VERSION 5.7 ;
  NOWIREEXTENSIONATPIN ON ;
  DIVIDERCHAR "/" ;
  BUSBITCHARS "[]" ;
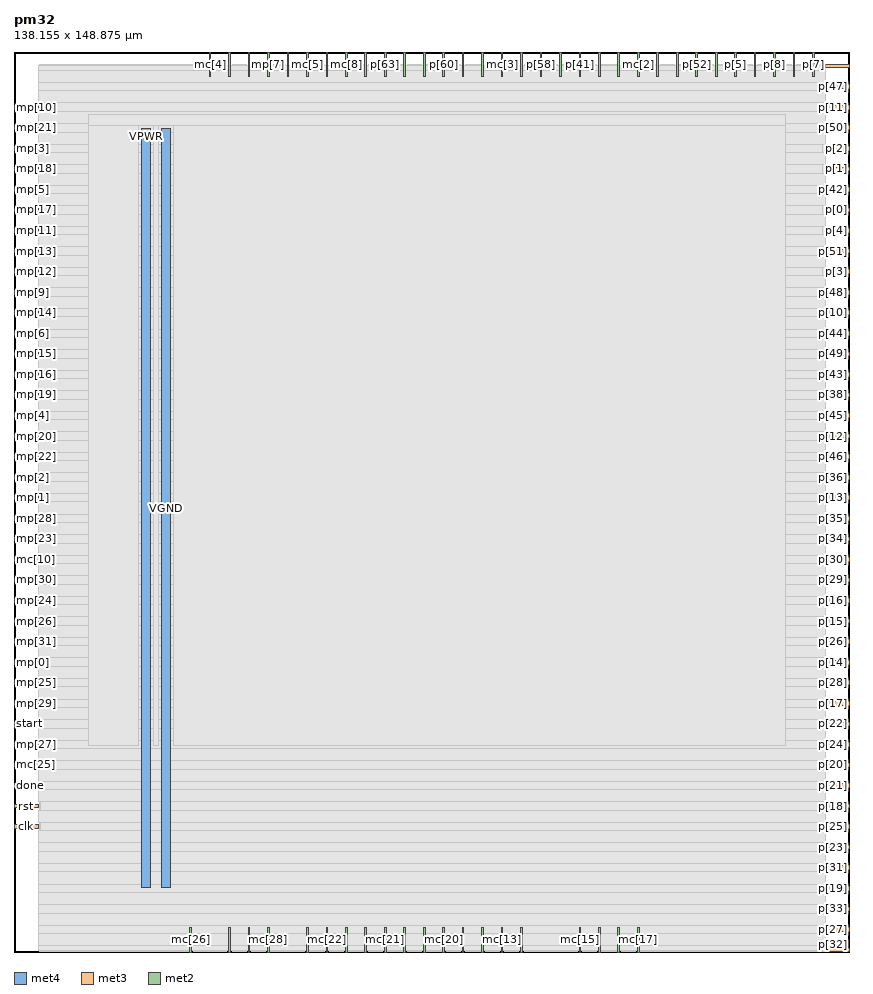
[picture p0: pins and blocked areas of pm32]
MACRO pm32
  CLASS BLOCK ;
  FOREIGN pm32 ;
  ORIGIN 0.000 0.000 ;
  SIZE 138.155 BY 148.875 ;
  PIN VGND
    DIRECTION INOUT ;
    USE GROUND ;
    PORT
      LAYER met4 ;
        RECT 24.340 10.640 25.940 136.240 ;
    END
  END VGND
  PIN VPWR
    DIRECTION INOUT ;
    USE POWER ;
    PORT
      LAYER met4 ;
        RECT 21.040 10.640 22.640 136.240 ;
    END
  END VPWR
  PIN clk
    DIRECTION INPUT ;
    USE SIGNAL ;
    ANTENNAGATEAREA 0.852000 ;
    PORT
      LAYER met3 ;
        RECT 0.000 20.440 4.000 21.040 ;
    END
  END clk
  PIN done
    DIRECTION OUTPUT ;
    USE SIGNAL ;
    ANTENNADIFFAREA 0.445500 ;
    PORT
      LAYER met3 ;
        RECT 0.000 27.240 4.000 27.840 ;
    END
  END done
  PIN mc[0]
    DIRECTION INPUT ;
    USE SIGNAL ;
    ANTENNAGATEAREA 0.196500 ;
    PORT
      LAYER met2 ;
        RECT 74.150 144.875 74.430 148.875 ;
    END
  END mc[0]
  PIN mc[10]
    DIRECTION INPUT ;
    USE SIGNAL ;
    ANTENNAGATEAREA 0.196500 ;
    PORT
      LAYER met3 ;
        RECT 0.000 64.640 4.000 65.240 ;
    END
  END mc[10]
  PIN mc[11]
    DIRECTION INPUT ;
    USE SIGNAL ;
    ANTENNAGATEAREA 0.196500 ;
    PORT
      LAYER met2 ;
        RECT 58.050 0.000 58.330 4.000 ;
    END
  END mc[11]
  PIN mc[12]
    DIRECTION INPUT ;
    USE SIGNAL ;
    ANTENNAGATEAREA 0.196500 ;
    PORT
      LAYER met2 ;
        RECT 74.150 0.000 74.430 4.000 ;
    END
  END mc[12]
  PIN mc[13]
    DIRECTION INPUT ;
    USE SIGNAL ;
    ANTENNAGATEAREA 0.196500 ;
    PORT
      LAYER met2 ;
        RECT 80.590 0.000 80.870 4.000 ;
    END
  END mc[13]
  PIN mc[14]
    DIRECTION INPUT ;
    USE SIGNAL ;
    ANTENNAGATEAREA 0.196500 ;
    PORT
      LAYER met2 ;
        RECT 77.370 0.000 77.650 4.000 ;
    END
  END mc[14]
  PIN mc[15]
    DIRECTION INPUT ;
    USE SIGNAL ;
    ANTENNAGATEAREA 0.196500 ;
    PORT
      LAYER met2 ;
        RECT 93.470 0.000 93.750 4.000 ;
    END
  END mc[15]
  PIN mc[16]
    DIRECTION INPUT ;
    USE SIGNAL ;
    ANTENNAGATEAREA 0.196500 ;
    PORT
      LAYER met2 ;
        RECT 99.910 0.000 100.190 4.000 ;
    END
  END mc[16]
  PIN mc[17]
    DIRECTION INPUT ;
    USE SIGNAL ;
    ANTENNAGATEAREA 0.196500 ;
    PORT
      LAYER met2 ;
        RECT 103.130 0.000 103.410 4.000 ;
    END
  END mc[17]
  PIN mc[18]
    DIRECTION INPUT ;
    USE SIGNAL ;
    ANTENNAGATEAREA 0.196500 ;
    PORT
      LAYER met2 ;
        RECT 96.690 0.000 96.970 4.000 ;
    END
  END mc[18]
  PIN mc[19]
    DIRECTION INPUT ;
    USE SIGNAL ;
    ANTENNAGATEAREA 0.196500 ;
    PORT
      LAYER met2 ;
        RECT 83.810 0.000 84.090 4.000 ;
    END
  END mc[19]
  PIN mc[1]
    DIRECTION INPUT ;
    USE SIGNAL ;
    ANTENNAGATEAREA 0.196500 ;
    PORT
      LAYER met2 ;
        RECT 116.010 144.875 116.290 148.875 ;
    END
  END mc[1]
  PIN mc[20]
    DIRECTION INPUT ;
    USE SIGNAL ;
    ANTENNAGATEAREA 0.196500 ;
    PORT
      LAYER met2 ;
        RECT 70.930 0.000 71.210 4.000 ;
    END
  END mc[20]
  PIN mc[21]
    DIRECTION INPUT ;
    USE SIGNAL ;
    ANTENNAGATEAREA 0.196500 ;
    PORT
      LAYER met2 ;
        RECT 61.270 0.000 61.550 4.000 ;
    END
  END mc[21]
  PIN mc[22]
    DIRECTION INPUT ;
    USE SIGNAL ;
    ANTENNAGATEAREA 0.196500 ;
    PORT
      LAYER met2 ;
        RECT 51.610 0.000 51.890 4.000 ;
    END
  END mc[22]
  PIN mc[23]
    DIRECTION INPUT ;
    USE SIGNAL ;
    ANTENNAGATEAREA 0.196500 ;
    PORT
      LAYER met2 ;
        RECT 48.390 0.000 48.670 4.000 ;
    END
  END mc[23]
  PIN mc[24]
    DIRECTION INPUT ;
    USE SIGNAL ;
    ANTENNAGATEAREA 0.196500 ;
    PORT
      LAYER met2 ;
        RECT 35.510 0.000 35.790 4.000 ;
    END
  END mc[24]
  PIN mc[25]
    DIRECTION INPUT ;
    USE SIGNAL ;
    ANTENNAGATEAREA 0.196500 ;
    PORT
      LAYER met3 ;
        RECT 0.000 30.640 4.000 31.240 ;
    END
  END mc[25]
  PIN mc[26]
    DIRECTION INPUT ;
    USE SIGNAL ;
    ANTENNAGATEAREA 0.196500 ;
    PORT
      LAYER met2 ;
        RECT 29.070 0.000 29.350 4.000 ;
    END
  END mc[26]
  PIN mc[27]
    DIRECTION INPUT ;
    USE SIGNAL ;
    ANTENNAGATEAREA 0.196500 ;
    PORT
      LAYER met2 ;
        RECT 38.730 0.000 39.010 4.000 ;
    END
  END mc[27]
  PIN mc[28]
    DIRECTION INPUT ;
    USE SIGNAL ;
    ANTENNAGATEAREA 0.196500 ;
    PORT
      LAYER met2 ;
        RECT 41.950 0.000 42.230 4.000 ;
    END
  END mc[28]
  PIN mc[29]
    DIRECTION INPUT ;
    USE SIGNAL ;
    ANTENNAGATEAREA 0.196500 ;
    PORT
      LAYER met2 ;
        RECT 67.710 0.000 67.990 4.000 ;
    END
  END mc[29]
  PIN mc[2]
    DIRECTION INPUT ;
    USE SIGNAL ;
    ANTENNAGATEAREA 0.196500 ;
    PORT
      LAYER met2 ;
        RECT 103.130 144.875 103.410 148.875 ;
    END
  END mc[2]
  PIN mc[30]
    DIRECTION INPUT ;
    USE SIGNAL ;
    ANTENNAGATEAREA 0.196500 ;
    PORT
      LAYER met2 ;
        RECT 64.490 0.000 64.770 4.000 ;
    END
  END mc[30]
  PIN mc[31]
    DIRECTION INPUT ;
    USE SIGNAL ;
    ANTENNAGATEAREA 0.196500 ;
    PORT
      LAYER met2 ;
        RECT 54.830 0.000 55.110 4.000 ;
    END
  END mc[31]
  PIN mc[3]
    DIRECTION INPUT ;
    USE SIGNAL ;
    ANTENNAGATEAREA 0.196500 ;
    PORT
      LAYER met2 ;
        RECT 80.590 144.875 80.870 148.875 ;
    END
  END mc[3]
  PIN mc[4]
    DIRECTION INPUT ;
    USE SIGNAL ;
    ANTENNAGATEAREA 0.196500 ;
    PORT
      LAYER met2 ;
        RECT 32.290 144.875 32.570 148.875 ;
    END
  END mc[4]
  PIN mc[5]
    DIRECTION INPUT ;
    USE SIGNAL ;
    ANTENNAGATEAREA 0.196500 ;
    PORT
      LAYER met2 ;
        RECT 48.390 144.875 48.670 148.875 ;
    END
  END mc[5]
  PIN mc[6]
    DIRECTION INPUT ;
    USE SIGNAL ;
    ANTENNAGATEAREA 0.196500 ;
    PORT
      LAYER met2 ;
        RECT 38.730 144.875 39.010 148.875 ;
    END
  END mc[6]
  PIN mc[7]
    DIRECTION INPUT ;
    USE SIGNAL ;
    ANTENNAGATEAREA 0.196500 ;
    PORT
      LAYER met2 ;
        RECT 45.170 144.875 45.450 148.875 ;
    END
  END mc[7]
  PIN mc[8]
    DIRECTION INPUT ;
    USE SIGNAL ;
    ANTENNAGATEAREA 0.196500 ;
    PORT
      LAYER met2 ;
        RECT 54.830 144.875 55.110 148.875 ;
    END
  END mc[8]
  PIN mc[9]
    DIRECTION INPUT ;
    USE SIGNAL ;
    ANTENNAGATEAREA 0.196500 ;
    PORT
      LAYER met2 ;
        RECT 58.050 144.875 58.330 148.875 ;
    END
  END mc[9]
  PIN mp[0]
    DIRECTION INPUT ;
    USE SIGNAL ;
    ANTENNAGATEAREA 0.196500 ;
    PORT
      LAYER met3 ;
        RECT 0.000 47.640 4.000 48.240 ;
    END
  END mp[0]
  PIN mp[10]
    DIRECTION INPUT ;
    USE SIGNAL ;
    ANTENNAGATEAREA 0.196500 ;
    PORT
      LAYER met3 ;
        RECT 0.000 139.440 4.000 140.040 ;
    END
  END mp[10]
  PIN mp[11]
    DIRECTION INPUT ;
    USE SIGNAL ;
    ANTENNAGATEAREA 0.196500 ;
    PORT
      LAYER met3 ;
        RECT 0.000 119.040 4.000 119.640 ;
    END
  END mp[11]
  PIN mp[12]
    DIRECTION INPUT ;
    USE SIGNAL ;
    ANTENNAGATEAREA 0.196500 ;
    PORT
      LAYER met3 ;
        RECT 0.000 112.240 4.000 112.840 ;
    END
  END mp[12]
  PIN mp[13]
    DIRECTION INPUT ;
    USE SIGNAL ;
    ANTENNAGATEAREA 0.196500 ;
    PORT
      LAYER met3 ;
        RECT 0.000 115.640 4.000 116.240 ;
    END
  END mp[13]
  PIN mp[14]
    DIRECTION INPUT ;
    USE SIGNAL ;
    ANTENNAGATEAREA 0.196500 ;
    PORT
      LAYER met3 ;
        RECT 0.000 105.440 4.000 106.040 ;
    END
  END mp[14]
  PIN mp[15]
    DIRECTION INPUT ;
    USE SIGNAL ;
    ANTENNAGATEAREA 0.196500 ;
    PORT
      LAYER met3 ;
        RECT 0.000 98.640 4.000 99.240 ;
    END
  END mp[15]
  PIN mp[16]
    DIRECTION INPUT ;
    USE SIGNAL ;
    ANTENNAGATEAREA 0.196500 ;
    PORT
      LAYER met3 ;
        RECT 0.000 95.240 4.000 95.840 ;
    END
  END mp[16]
  PIN mp[17]
    DIRECTION INPUT ;
    USE SIGNAL ;
    ANTENNAGATEAREA 0.196500 ;
    PORT
      LAYER met3 ;
        RECT 0.000 122.440 4.000 123.040 ;
    END
  END mp[17]
  PIN mp[18]
    DIRECTION INPUT ;
    USE SIGNAL ;
    ANTENNAGATEAREA 0.196500 ;
    PORT
      LAYER met3 ;
        RECT 0.000 129.240 4.000 129.840 ;
    END
  END mp[18]
  PIN mp[19]
    DIRECTION INPUT ;
    USE SIGNAL ;
    ANTENNAGATEAREA 0.196500 ;
    PORT
      LAYER met3 ;
        RECT 0.000 91.840 4.000 92.440 ;
    END
  END mp[19]
  PIN mp[1]
    DIRECTION INPUT ;
    USE SIGNAL ;
    ANTENNAGATEAREA 0.196500 ;
    PORT
      LAYER met3 ;
        RECT 0.000 74.840 4.000 75.440 ;
    END
  END mp[1]
  PIN mp[20]
    DIRECTION INPUT ;
    USE SIGNAL ;
    ANTENNAGATEAREA 0.196500 ;
    PORT
      LAYER met3 ;
        RECT 0.000 85.040 4.000 85.640 ;
    END
  END mp[20]
  PIN mp[21]
    DIRECTION INPUT ;
    USE SIGNAL ;
    ANTENNAGATEAREA 0.196500 ;
    PORT
      LAYER met3 ;
        RECT 0.000 136.040 4.000 136.640 ;
    END
  END mp[21]
  PIN mp[22]
    DIRECTION INPUT ;
    USE SIGNAL ;
    ANTENNAGATEAREA 0.196500 ;
    PORT
      LAYER met3 ;
        RECT 0.000 81.640 4.000 82.240 ;
    END
  END mp[22]
  PIN mp[23]
    DIRECTION INPUT ;
    USE SIGNAL ;
    ANTENNAGATEAREA 0.196500 ;
    PORT
      LAYER met3 ;
        RECT 0.000 68.040 4.000 68.640 ;
    END
  END mp[23]
  PIN mp[24]
    DIRECTION INPUT ;
    USE SIGNAL ;
    ANTENNAGATEAREA 0.196500 ;
    PORT
      LAYER met3 ;
        RECT 0.000 57.840 4.000 58.440 ;
    END
  END mp[24]
  PIN mp[25]
    DIRECTION INPUT ;
    USE SIGNAL ;
    ANTENNAGATEAREA 0.196500 ;
    PORT
      LAYER met3 ;
        RECT 0.000 44.240 4.000 44.840 ;
    END
  END mp[25]
  PIN mp[26]
    DIRECTION INPUT ;
    USE SIGNAL ;
    ANTENNAGATEAREA 0.196500 ;
    PORT
      LAYER met3 ;
        RECT 0.000 54.440 4.000 55.040 ;
    END
  END mp[26]
  PIN mp[27]
    DIRECTION INPUT ;
    USE SIGNAL ;
    ANTENNAGATEAREA 0.196500 ;
    PORT
      LAYER met3 ;
        RECT 0.000 34.040 4.000 34.640 ;
    END
  END mp[27]
  PIN mp[28]
    DIRECTION INPUT ;
    USE SIGNAL ;
    ANTENNAGATEAREA 0.196500 ;
    PORT
      LAYER met3 ;
        RECT 0.000 71.440 4.000 72.040 ;
    END
  END mp[28]
  PIN mp[29]
    DIRECTION INPUT ;
    USE SIGNAL ;
    ANTENNAGATEAREA 0.196500 ;
    PORT
      LAYER met3 ;
        RECT 0.000 40.840 4.000 41.440 ;
    END
  END mp[29]
  PIN mp[2]
    DIRECTION INPUT ;
    USE SIGNAL ;
    ANTENNAGATEAREA 0.196500 ;
    PORT
      LAYER met3 ;
        RECT 0.000 78.240 4.000 78.840 ;
    END
  END mp[2]
  PIN mp[30]
    DIRECTION INPUT ;
    USE SIGNAL ;
    ANTENNAGATEAREA 0.196500 ;
    PORT
      LAYER met3 ;
        RECT 0.000 61.240 4.000 61.840 ;
    END
  END mp[30]
  PIN mp[31]
    DIRECTION INPUT ;
    USE SIGNAL ;
    ANTENNAGATEAREA 0.196500 ;
    PORT
      LAYER met3 ;
        RECT 0.000 51.040 4.000 51.640 ;
    END
  END mp[31]
  PIN mp[3]
    DIRECTION INPUT ;
    USE SIGNAL ;
    ANTENNAGATEAREA 0.196500 ;
    PORT
      LAYER met3 ;
        RECT 0.000 132.640 4.000 133.240 ;
    END
  END mp[3]
  PIN mp[4]
    DIRECTION INPUT ;
    USE SIGNAL ;
    ANTENNAGATEAREA 0.196500 ;
    PORT
      LAYER met3 ;
        RECT 0.000 88.440 4.000 89.040 ;
    END
  END mp[4]
  PIN mp[5]
    DIRECTION INPUT ;
    USE SIGNAL ;
    ANTENNAGATEAREA 0.196500 ;
    PORT
      LAYER met3 ;
        RECT 0.000 125.840 4.000 126.440 ;
    END
  END mp[5]
  PIN mp[6]
    DIRECTION INPUT ;
    USE SIGNAL ;
    ANTENNAGATEAREA 0.196500 ;
    PORT
      LAYER met3 ;
        RECT 0.000 102.040 4.000 102.640 ;
    END
  END mp[6]
  PIN mp[7]
    DIRECTION INPUT ;
    USE SIGNAL ;
    ANTENNAGATEAREA 0.196500 ;
    PORT
      LAYER met2 ;
        RECT 41.950 144.875 42.230 148.875 ;
    END
  END mp[7]
  PIN mp[8]
    DIRECTION INPUT ;
    USE SIGNAL ;
    ANTENNAGATEAREA 0.196500 ;
    PORT
      LAYER met2 ;
        RECT 35.510 144.875 35.790 148.875 ;
    END
  END mp[8]
  PIN mp[9]
    DIRECTION INPUT ;
    USE SIGNAL ;
    ANTENNAGATEAREA 0.196500 ;
    PORT
      LAYER met3 ;
        RECT 0.000 108.840 4.000 109.440 ;
    END
  END mp[9]
  PIN p[0]
    DIRECTION OUTPUT ;
    USE SIGNAL ;
    ANTENNADIFFAREA 0.445500 ;
    PORT
      LAYER met3 ;
        RECT 134.155 122.440 138.155 123.040 ;
    END
  END p[0]
  PIN p[10]
    DIRECTION OUTPUT ;
    USE SIGNAL ;
    ANTENNADIFFAREA 0.445500 ;
    PORT
      LAYER met3 ;
        RECT 134.155 105.440 138.155 106.040 ;
    END
  END p[10]
  PIN p[11]
    DIRECTION OUTPUT ;
    USE SIGNAL ;
    ANTENNADIFFAREA 0.445500 ;
    PORT
      LAYER met3 ;
        RECT 134.155 139.440 138.155 140.040 ;
    END
  END p[11]
  PIN p[12]
    DIRECTION OUTPUT ;
    USE SIGNAL ;
    ANTENNADIFFAREA 0.445500 ;
    PORT
      LAYER met3 ;
        RECT 134.155 85.040 138.155 85.640 ;
    END
  END p[12]
  PIN p[13]
    DIRECTION OUTPUT ;
    USE SIGNAL ;
    ANTENNADIFFAREA 0.445500 ;
    PORT
      LAYER met3 ;
        RECT 134.155 74.840 138.155 75.440 ;
    END
  END p[13]
  PIN p[14]
    DIRECTION OUTPUT ;
    USE SIGNAL ;
    ANTENNADIFFAREA 0.445500 ;
    PORT
      LAYER met3 ;
        RECT 134.155 47.640 138.155 48.240 ;
    END
  END p[14]
  PIN p[15]
    DIRECTION OUTPUT ;
    USE SIGNAL ;
    ANTENNADIFFAREA 0.445500 ;
    PORT
      LAYER met3 ;
        RECT 134.155 54.440 138.155 55.040 ;
    END
  END p[15]
  PIN p[16]
    DIRECTION OUTPUT ;
    USE SIGNAL ;
    ANTENNADIFFAREA 0.445500 ;
    PORT
      LAYER met3 ;
        RECT 134.155 57.840 138.155 58.440 ;
    END
  END p[16]
  PIN p[17]
    DIRECTION OUTPUT ;
    USE SIGNAL ;
    ANTENNADIFFAREA 0.445500 ;
    PORT
      LAYER met3 ;
        RECT 134.155 40.840 138.155 41.440 ;
    END
  END p[17]
  PIN p[18]
    DIRECTION OUTPUT ;
    USE SIGNAL ;
    ANTENNADIFFAREA 0.445500 ;
    PORT
      LAYER met3 ;
        RECT 134.155 23.840 138.155 24.440 ;
    END
  END p[18]
  PIN p[19]
    DIRECTION OUTPUT ;
    USE SIGNAL ;
    ANTENNADIFFAREA 0.445500 ;
    PORT
      LAYER met3 ;
        RECT 134.155 10.240 138.155 10.840 ;
    END
  END p[19]
  PIN p[1]
    DIRECTION OUTPUT ;
    USE SIGNAL ;
    ANTENNADIFFAREA 0.445500 ;
    PORT
      LAYER met3 ;
        RECT 134.155 129.240 138.155 129.840 ;
    END
  END p[1]
  PIN p[20]
    DIRECTION OUTPUT ;
    USE SIGNAL ;
    ANTENNADIFFAREA 0.445500 ;
    PORT
      LAYER met3 ;
        RECT 134.155 30.640 138.155 31.240 ;
    END
  END p[20]
  PIN p[21]
    DIRECTION OUTPUT ;
    USE SIGNAL ;
    ANTENNADIFFAREA 0.445500 ;
    PORT
      LAYER met3 ;
        RECT 134.155 27.240 138.155 27.840 ;
    END
  END p[21]
  PIN p[22]
    DIRECTION OUTPUT ;
    USE SIGNAL ;
    ANTENNADIFFAREA 0.445500 ;
    PORT
      LAYER met3 ;
        RECT 134.155 37.440 138.155 38.040 ;
    END
  END p[22]
  PIN p[23]
    DIRECTION OUTPUT ;
    USE SIGNAL ;
    ANTENNADIFFAREA 0.445500 ;
    PORT
      LAYER met3 ;
        RECT 134.155 17.040 138.155 17.640 ;
    END
  END p[23]
  PIN p[24]
    DIRECTION OUTPUT ;
    USE SIGNAL ;
    ANTENNADIFFAREA 0.445500 ;
    PORT
      LAYER met3 ;
        RECT 134.155 34.040 138.155 34.640 ;
    END
  END p[24]
  PIN p[25]
    DIRECTION OUTPUT ;
    USE SIGNAL ;
    ANTENNADIFFAREA 0.445500 ;
    PORT
      LAYER met3 ;
        RECT 134.155 20.440 138.155 21.040 ;
    END
  END p[25]
  PIN p[26]
    DIRECTION OUTPUT ;
    USE SIGNAL ;
    ANTENNADIFFAREA 0.445500 ;
    PORT
      LAYER met3 ;
        RECT 134.155 51.040 138.155 51.640 ;
    END
  END p[26]
  PIN p[27]
    DIRECTION OUTPUT ;
    USE SIGNAL ;
    ANTENNADIFFAREA 0.445500 ;
    PORT
      LAYER met3 ;
        RECT 134.155 3.440 138.155 4.040 ;
    END
  END p[27]
  PIN p[28]
    DIRECTION OUTPUT ;
    USE SIGNAL ;
    ANTENNADIFFAREA 0.445500 ;
    PORT
      LAYER met3 ;
        RECT 134.155 44.240 138.155 44.840 ;
    END
  END p[28]
  PIN p[29]
    DIRECTION OUTPUT ;
    USE SIGNAL ;
    ANTENNADIFFAREA 0.445500 ;
    PORT
      LAYER met3 ;
        RECT 134.155 61.240 138.155 61.840 ;
    END
  END p[29]
  PIN p[2]
    DIRECTION OUTPUT ;
    USE SIGNAL ;
    ANTENNADIFFAREA 0.445500 ;
    PORT
      LAYER met3 ;
        RECT 134.155 132.640 138.155 133.240 ;
    END
  END p[2]
  PIN p[30]
    DIRECTION OUTPUT ;
    USE SIGNAL ;
    ANTENNADIFFAREA 0.445500 ;
    PORT
      LAYER met3 ;
        RECT 134.155 64.640 138.155 65.240 ;
    END
  END p[30]
  PIN p[31]
    DIRECTION OUTPUT ;
    USE SIGNAL ;
    ANTENNADIFFAREA 0.445500 ;
    PORT
      LAYER met3 ;
        RECT 134.155 13.640 138.155 14.240 ;
    END
  END p[31]
  PIN p[32]
    DIRECTION OUTPUT ;
    USE SIGNAL ;
    ANTENNADIFFAREA 0.445500 ;
    PORT
      LAYER met3 ;
        RECT 134.155 0.040 138.155 0.640 ;
    END
  END p[32]
  PIN p[33]
    DIRECTION OUTPUT ;
    USE SIGNAL ;
    ANTENNADIFFAREA 0.445500 ;
    PORT
      LAYER met3 ;
        RECT 134.155 6.840 138.155 7.440 ;
    END
  END p[33]
  PIN p[34]
    DIRECTION OUTPUT ;
    USE SIGNAL ;
    ANTENNADIFFAREA 0.445500 ;
    PORT
      LAYER met3 ;
        RECT 134.155 68.040 138.155 68.640 ;
    END
  END p[34]
  PIN p[35]
    DIRECTION OUTPUT ;
    USE SIGNAL ;
    ANTENNADIFFAREA 0.445500 ;
    PORT
      LAYER met3 ;
        RECT 134.155 71.440 138.155 72.040 ;
    END
  END p[35]
  PIN p[36]
    DIRECTION OUTPUT ;
    USE SIGNAL ;
    ANTENNADIFFAREA 0.445500 ;
    PORT
      LAYER met3 ;
        RECT 134.155 78.240 138.155 78.840 ;
    END
  END p[36]
  PIN p[37]
    DIRECTION OUTPUT ;
    USE SIGNAL ;
    ANTENNADIFFAREA 0.445500 ;
    PORT
      LAYER met3 ;
        RECT 134.155 146.240 138.155 146.840 ;
    END
  END p[37]
  PIN p[38]
    DIRECTION OUTPUT ;
    USE SIGNAL ;
    ANTENNADIFFAREA 0.445500 ;
    PORT
      LAYER met3 ;
        RECT 134.155 91.840 138.155 92.440 ;
    END
  END p[38]
  PIN p[39]
    DIRECTION OUTPUT ;
    USE SIGNAL ;
    ANTENNADIFFAREA 0.445500 ;
    PORT
      LAYER met2 ;
        RECT 77.370 144.875 77.650 148.875 ;
    END
  END p[39]
  PIN p[3]
    DIRECTION OUTPUT ;
    USE SIGNAL ;
    ANTENNADIFFAREA 0.445500 ;
    PORT
      LAYER met3 ;
        RECT 134.155 112.240 138.155 112.840 ;
    END
  END p[3]
  PIN p[40]
    DIRECTION OUTPUT ;
    USE SIGNAL ;
    ANTENNADIFFAREA 0.445500 ;
    PORT
      LAYER met2 ;
        RECT 51.610 144.875 51.890 148.875 ;
    END
  END p[40]
  PIN p[41]
    DIRECTION OUTPUT ;
    USE SIGNAL ;
    ANTENNADIFFAREA 0.445500 ;
    PORT
      LAYER met2 ;
        RECT 93.470 144.875 93.750 148.875 ;
    END
  END p[41]
  PIN p[42]
    DIRECTION OUTPUT ;
    USE SIGNAL ;
    ANTENNADIFFAREA 0.445500 ;
    PORT
      LAYER met3 ;
        RECT 134.155 125.840 138.155 126.440 ;
    END
  END p[42]
  PIN p[43]
    DIRECTION OUTPUT ;
    USE SIGNAL ;
    ANTENNADIFFAREA 0.445500 ;
    PORT
      LAYER met3 ;
        RECT 134.155 95.240 138.155 95.840 ;
    END
  END p[43]
  PIN p[44]
    DIRECTION OUTPUT ;
    USE SIGNAL ;
    ANTENNADIFFAREA 0.445500 ;
    PORT
      LAYER met3 ;
        RECT 134.155 102.040 138.155 102.640 ;
    END
  END p[44]
  PIN p[45]
    DIRECTION OUTPUT ;
    USE SIGNAL ;
    ANTENNADIFFAREA 0.445500 ;
    PORT
      LAYER met3 ;
        RECT 134.155 88.440 138.155 89.040 ;
    END
  END p[45]
  PIN p[46]
    DIRECTION OUTPUT ;
    USE SIGNAL ;
    ANTENNADIFFAREA 0.445500 ;
    PORT
      LAYER met3 ;
        RECT 134.155 81.640 138.155 82.240 ;
    END
  END p[46]
  PIN p[47]
    DIRECTION OUTPUT ;
    USE SIGNAL ;
    ANTENNADIFFAREA 0.445500 ;
    PORT
      LAYER met3 ;
        RECT 134.155 142.840 138.155 143.440 ;
    END
  END p[47]
  PIN p[48]
    DIRECTION OUTPUT ;
    USE SIGNAL ;
    ANTENNADIFFAREA 0.445500 ;
    PORT
      LAYER met3 ;
        RECT 134.155 108.840 138.155 109.440 ;
    END
  END p[48]
  PIN p[49]
    DIRECTION OUTPUT ;
    USE SIGNAL ;
    ANTENNADIFFAREA 0.445500 ;
    PORT
      LAYER met3 ;
        RECT 134.155 98.640 138.155 99.240 ;
    END
  END p[49]
  PIN p[4]
    DIRECTION OUTPUT ;
    USE SIGNAL ;
    ANTENNADIFFAREA 0.445500 ;
    PORT
      LAYER met3 ;
        RECT 134.155 119.040 138.155 119.640 ;
    END
  END p[4]
  PIN p[50]
    DIRECTION OUTPUT ;
    USE SIGNAL ;
    ANTENNADIFFAREA 0.445500 ;
    PORT
      LAYER met3 ;
        RECT 134.155 136.040 138.155 136.640 ;
    END
  END p[50]
  PIN p[51]
    DIRECTION OUTPUT ;
    USE SIGNAL ;
    ANTENNADIFFAREA 0.445500 ;
    PORT
      LAYER met3 ;
        RECT 134.155 115.640 138.155 116.240 ;
    END
  END p[51]
  PIN p[52]
    DIRECTION OUTPUT ;
    USE SIGNAL ;
    ANTENNADIFFAREA 0.445500 ;
    PORT
      LAYER met2 ;
        RECT 112.790 144.875 113.070 148.875 ;
    END
  END p[52]
  PIN p[53]
    DIRECTION OUTPUT ;
    USE SIGNAL ;
    ANTENNADIFFAREA 0.445500 ;
    PORT
      LAYER met2 ;
        RECT 109.570 144.875 109.850 148.875 ;
    END
  END p[53]
  PIN p[54]
    DIRECTION OUTPUT ;
    USE SIGNAL ;
    ANTENNADIFFAREA 0.445500 ;
    PORT
      LAYER met2 ;
        RECT 106.350 144.875 106.630 148.875 ;
    END
  END p[54]
  PIN p[55]
    DIRECTION OUTPUT ;
    USE SIGNAL ;
    ANTENNADIFFAREA 0.445500 ;
    PORT
      LAYER met2 ;
        RECT 99.910 144.875 100.190 148.875 ;
    END
  END p[55]
  PIN p[56]
    DIRECTION OUTPUT ;
    USE SIGNAL ;
    ANTENNADIFFAREA 0.445500 ;
    PORT
      LAYER met2 ;
        RECT 96.690 144.875 96.970 148.875 ;
    END
  END p[56]
  PIN p[57]
    DIRECTION OUTPUT ;
    USE SIGNAL ;
    ANTENNADIFFAREA 0.445500 ;
    PORT
      LAYER met2 ;
        RECT 90.250 144.875 90.530 148.875 ;
    END
  END p[57]
  PIN p[58]
    DIRECTION OUTPUT ;
    USE SIGNAL ;
    ANTENNADIFFAREA 0.445500 ;
    PORT
      LAYER met2 ;
        RECT 87.030 144.875 87.310 148.875 ;
    END
  END p[58]
  PIN p[59]
    DIRECTION OUTPUT ;
    USE SIGNAL ;
    ANTENNADIFFAREA 0.445500 ;
    PORT
      LAYER met2 ;
        RECT 83.810 144.875 84.090 148.875 ;
    END
  END p[59]
  PIN p[5]
    DIRECTION OUTPUT ;
    USE SIGNAL ;
    ANTENNADIFFAREA 0.445500 ;
    PORT
      LAYER met2 ;
        RECT 119.230 144.875 119.510 148.875 ;
    END
  END p[5]
  PIN p[60]
    DIRECTION OUTPUT ;
    USE SIGNAL ;
    ANTENNADIFFAREA 0.445500 ;
    PORT
      LAYER met2 ;
        RECT 70.930 144.875 71.210 148.875 ;
    END
  END p[60]
  PIN p[61]
    DIRECTION OUTPUT ;
    USE SIGNAL ;
    ANTENNADIFFAREA 0.445500 ;
    PORT
      LAYER met2 ;
        RECT 67.710 144.875 67.990 148.875 ;
    END
  END p[61]
  PIN p[62]
    DIRECTION OUTPUT ;
    USE SIGNAL ;
    ANTENNADIFFAREA 0.445500 ;
    PORT
      LAYER met2 ;
        RECT 64.490 144.875 64.770 148.875 ;
    END
  END p[62]
  PIN p[63]
    DIRECTION OUTPUT ;
    USE SIGNAL ;
    ANTENNADIFFAREA 0.445500 ;
    PORT
      LAYER met2 ;
        RECT 61.270 144.875 61.550 148.875 ;
    END
  END p[63]
  PIN p[6]
    DIRECTION OUTPUT ;
    USE SIGNAL ;
    ANTENNADIFFAREA 0.445500 ;
    PORT
      LAYER met2 ;
        RECT 128.890 144.875 129.170 148.875 ;
    END
  END p[6]
  PIN p[7]
    DIRECTION OUTPUT ;
    USE SIGNAL ;
    ANTENNADIFFAREA 0.445500 ;
    PORT
      LAYER met2 ;
        RECT 132.110 144.875 132.390 148.875 ;
    END
  END p[7]
  PIN p[8]
    DIRECTION OUTPUT ;
    USE SIGNAL ;
    ANTENNADIFFAREA 0.445500 ;
    PORT
      LAYER met2 ;
        RECT 125.670 144.875 125.950 148.875 ;
    END
  END p[8]
  PIN p[9]
    DIRECTION OUTPUT ;
    USE SIGNAL ;
    ANTENNADIFFAREA 0.445500 ;
    PORT
      LAYER met2 ;
        RECT 122.450 144.875 122.730 148.875 ;
    END
  END p[9]
  PIN rst
    DIRECTION INPUT ;
    USE SIGNAL ;
    ANTENNAGATEAREA 0.196500 ;
    PORT
      LAYER met3 ;
        RECT 0.000 23.840 4.000 24.440 ;
    END
  END rst
  PIN start
    DIRECTION INPUT ;
    USE SIGNAL ;
    ANTENNAGATEAREA 0.213000 ;
    PORT
      LAYER met3 ;
        RECT 0.000 37.440 4.000 38.040 ;
    END
  END start
  OBS
      LAYER nwell ;
        RECT 5.330 10.795 132.670 136.085 ;
      LAYER li1 ;
        RECT 5.520 10.795 132.480 136.085 ;
      LAYER met1 ;
        RECT 4.210 8.880 134.250 144.800 ;
      LAYER met2 ;
        RECT 4.230 144.595 32.010 146.725 ;
        RECT 32.850 144.595 35.230 146.725 ;
        RECT 36.070 144.595 38.450 146.725 ;
        RECT 39.290 144.595 41.670 146.725 ;
        RECT 42.510 144.595 44.890 146.725 ;
        RECT 45.730 144.595 48.110 146.725 ;
        RECT 48.950 144.595 51.330 146.725 ;
        RECT 52.170 144.595 54.550 146.725 ;
        RECT 55.390 144.595 57.770 146.725 ;
        RECT 58.610 144.595 60.990 146.725 ;
        RECT 61.830 144.595 64.210 146.725 ;
        RECT 65.050 144.595 67.430 146.725 ;
        RECT 68.270 144.595 70.650 146.725 ;
        RECT 71.490 144.595 73.870 146.725 ;
        RECT 74.710 144.595 77.090 146.725 ;
        RECT 77.930 144.595 80.310 146.725 ;
        RECT 81.150 144.595 83.530 146.725 ;
        RECT 84.370 144.595 86.750 146.725 ;
        RECT 87.590 144.595 89.970 146.725 ;
        RECT 90.810 144.595 93.190 146.725 ;
        RECT 94.030 144.595 96.410 146.725 ;
        RECT 97.250 144.595 99.630 146.725 ;
        RECT 100.470 144.595 102.850 146.725 ;
        RECT 103.690 144.595 106.070 146.725 ;
        RECT 106.910 144.595 109.290 146.725 ;
        RECT 110.130 144.595 112.510 146.725 ;
        RECT 113.350 144.595 115.730 146.725 ;
        RECT 116.570 144.595 118.950 146.725 ;
        RECT 119.790 144.595 122.170 146.725 ;
        RECT 123.010 144.595 125.390 146.725 ;
        RECT 126.230 144.595 128.610 146.725 ;
        RECT 129.450 144.595 131.830 146.725 ;
        RECT 132.670 144.595 134.230 146.725 ;
        RECT 4.230 4.280 134.230 144.595 ;
        RECT 4.230 0.155 28.790 4.280 ;
        RECT 29.630 0.155 35.230 4.280 ;
        RECT 36.070 0.155 38.450 4.280 ;
        RECT 39.290 0.155 41.670 4.280 ;
        RECT 42.510 0.155 48.110 4.280 ;
        RECT 48.950 0.155 51.330 4.280 ;
        RECT 52.170 0.155 54.550 4.280 ;
        RECT 55.390 0.155 57.770 4.280 ;
        RECT 58.610 0.155 60.990 4.280 ;
        RECT 61.830 0.155 64.210 4.280 ;
        RECT 65.050 0.155 67.430 4.280 ;
        RECT 68.270 0.155 70.650 4.280 ;
        RECT 71.490 0.155 73.870 4.280 ;
        RECT 74.710 0.155 77.090 4.280 ;
        RECT 77.930 0.155 80.310 4.280 ;
        RECT 81.150 0.155 83.530 4.280 ;
        RECT 84.370 0.155 93.190 4.280 ;
        RECT 94.030 0.155 96.410 4.280 ;
        RECT 97.250 0.155 99.630 4.280 ;
        RECT 100.470 0.155 102.850 4.280 ;
        RECT 103.690 0.155 134.230 4.280 ;
      LAYER met3 ;
        RECT 3.990 145.840 133.755 146.705 ;
        RECT 3.990 143.840 134.155 145.840 ;
        RECT 3.990 142.440 133.755 143.840 ;
        RECT 3.990 140.440 134.155 142.440 ;
        RECT 4.400 139.040 133.755 140.440 ;
        RECT 3.990 137.040 134.155 139.040 ;
        RECT 4.400 135.640 133.755 137.040 ;
        RECT 3.990 133.640 134.155 135.640 ;
        RECT 4.400 132.240 133.755 133.640 ;
        RECT 3.990 130.240 134.155 132.240 ;
        RECT 4.400 128.840 133.755 130.240 ;
        RECT 3.990 126.840 134.155 128.840 ;
        RECT 4.400 125.440 133.755 126.840 ;
        RECT 3.990 123.440 134.155 125.440 ;
        RECT 4.400 122.040 133.755 123.440 ;
        RECT 3.990 120.040 134.155 122.040 ;
        RECT 4.400 118.640 133.755 120.040 ;
        RECT 3.990 116.640 134.155 118.640 ;
        RECT 4.400 115.240 133.755 116.640 ;
        RECT 3.990 113.240 134.155 115.240 ;
        RECT 4.400 111.840 133.755 113.240 ;
        RECT 3.990 109.840 134.155 111.840 ;
        RECT 4.400 108.440 133.755 109.840 ;
        RECT 3.990 106.440 134.155 108.440 ;
        RECT 4.400 105.040 133.755 106.440 ;
        RECT 3.990 103.040 134.155 105.040 ;
        RECT 4.400 101.640 133.755 103.040 ;
        RECT 3.990 99.640 134.155 101.640 ;
        RECT 4.400 98.240 133.755 99.640 ;
        RECT 3.990 96.240 134.155 98.240 ;
        RECT 4.400 94.840 133.755 96.240 ;
        RECT 3.990 92.840 134.155 94.840 ;
        RECT 4.400 91.440 133.755 92.840 ;
        RECT 3.990 89.440 134.155 91.440 ;
        RECT 4.400 88.040 133.755 89.440 ;
        RECT 3.990 86.040 134.155 88.040 ;
        RECT 4.400 84.640 133.755 86.040 ;
        RECT 3.990 82.640 134.155 84.640 ;
        RECT 4.400 81.240 133.755 82.640 ;
        RECT 3.990 79.240 134.155 81.240 ;
        RECT 4.400 77.840 133.755 79.240 ;
        RECT 3.990 75.840 134.155 77.840 ;
        RECT 4.400 74.440 133.755 75.840 ;
        RECT 3.990 72.440 134.155 74.440 ;
        RECT 4.400 71.040 133.755 72.440 ;
        RECT 3.990 69.040 134.155 71.040 ;
        RECT 4.400 67.640 133.755 69.040 ;
        RECT 3.990 65.640 134.155 67.640 ;
        RECT 4.400 64.240 133.755 65.640 ;
        RECT 3.990 62.240 134.155 64.240 ;
        RECT 4.400 60.840 133.755 62.240 ;
        RECT 3.990 58.840 134.155 60.840 ;
        RECT 4.400 57.440 133.755 58.840 ;
        RECT 3.990 55.440 134.155 57.440 ;
        RECT 4.400 54.040 133.755 55.440 ;
        RECT 3.990 52.040 134.155 54.040 ;
        RECT 4.400 50.640 133.755 52.040 ;
        RECT 3.990 48.640 134.155 50.640 ;
        RECT 4.400 47.240 133.755 48.640 ;
        RECT 3.990 45.240 134.155 47.240 ;
        RECT 4.400 43.840 133.755 45.240 ;
        RECT 3.990 41.840 134.155 43.840 ;
        RECT 4.400 40.440 133.755 41.840 ;
        RECT 3.990 38.440 134.155 40.440 ;
        RECT 4.400 37.040 133.755 38.440 ;
        RECT 3.990 35.040 134.155 37.040 ;
        RECT 4.400 33.640 133.755 35.040 ;
        RECT 3.990 31.640 134.155 33.640 ;
        RECT 4.400 30.240 133.755 31.640 ;
        RECT 3.990 28.240 134.155 30.240 ;
        RECT 4.400 26.840 133.755 28.240 ;
        RECT 3.990 24.840 134.155 26.840 ;
        RECT 4.400 23.440 133.755 24.840 ;
        RECT 3.990 21.440 134.155 23.440 ;
        RECT 4.400 20.040 133.755 21.440 ;
        RECT 3.990 18.040 134.155 20.040 ;
        RECT 3.990 16.640 133.755 18.040 ;
        RECT 3.990 14.640 134.155 16.640 ;
        RECT 3.990 13.240 133.755 14.640 ;
        RECT 3.990 11.240 134.155 13.240 ;
        RECT 3.990 9.840 133.755 11.240 ;
        RECT 3.990 7.840 134.155 9.840 ;
        RECT 3.990 6.440 133.755 7.840 ;
        RECT 3.990 4.440 134.155 6.440 ;
        RECT 3.990 3.040 133.755 4.440 ;
        RECT 3.990 1.040 134.155 3.040 ;
        RECT 3.990 0.175 133.755 1.040 ;
      LAYER met4 ;
        RECT 12.255 136.640 127.585 138.545 ;
        RECT 12.255 34.175 20.640 136.640 ;
        RECT 23.040 34.175 23.940 136.640 ;
        RECT 26.340 34.175 127.585 136.640 ;
  END
END pm32
END LIBRARY

